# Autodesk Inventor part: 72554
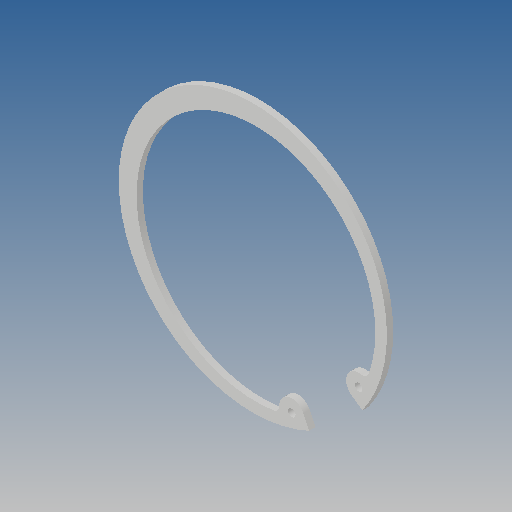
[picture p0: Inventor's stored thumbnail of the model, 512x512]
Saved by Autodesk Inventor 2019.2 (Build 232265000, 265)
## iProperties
Created: 2013-07
Part Number: 72554
Material: Ogólny
Document SubType Name: Modeling
Designer: CADENGINEERING4
Density: 1 g/cm^3
Appearance: Domyślna
Author: CADENGINEERING4
Revision Number: ÈÎºÎ
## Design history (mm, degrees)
feature "circlips for holes--type a gb_GB_CONNECTING_PIECE_RING_RRH 1"
node "Bryła1"
